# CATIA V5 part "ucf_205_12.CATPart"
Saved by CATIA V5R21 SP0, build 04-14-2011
Part number: ucf_205_12
Bounding box of the stored display mesh (mm): x -7.104 to 0.331, y -3.969 to 3.969, z 15.486 to 22.921
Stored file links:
  C:\TPO v2\SharedFS\Outgoing\ucf_205_12.CATPart

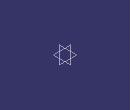
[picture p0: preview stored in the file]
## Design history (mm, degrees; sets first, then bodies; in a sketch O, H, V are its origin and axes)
AxisSystem1: origin (0, 0, 0), X (1, 0, 0), Y (0, 1, 0), Z (0, 0, 1)
Body1 "ucf_205_12" (main body)
  Solid1: solid without history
